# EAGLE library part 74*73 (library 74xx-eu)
Dual J-K FLIP FLOP, clear

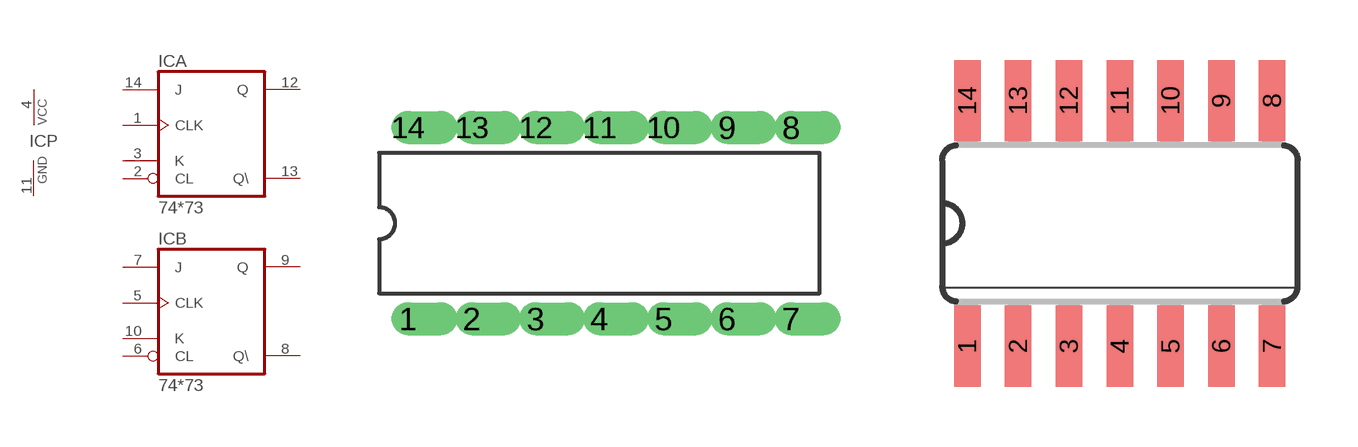
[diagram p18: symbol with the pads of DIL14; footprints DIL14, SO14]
Designator prefix IC; gates A=7473 B=7473 P=PWRN

## 74HC73N, 74HCT73N, 74LS73N  [DIL14]
1  A:CLK  in
2  A:CL  in
3  A:K  in
4  P:VCC  pwr
5  B:CLK  in
6  B:CL  in
7  B:J  in
8  B:Q\  out
9  B:Q  out
10  B:K  in
11  P:GND  pwr
12  A:Q  out
13  A:Q\  out
14  A:J  in

## 74HC73D, 74HCT73D, 74LS73D  [SO14]
Pads as for DIL14

## Footprint DIL14 (pad centres in mm)
Dual In Line
drill 0.8 offset: 1 -7.62,-3.81; 2 -5.08,-3.81; 3 -2.54,-3.81; 4 0,-3.81; 5 2.54,-3.81; 6 5.08,-3.81; 7 7.62,-3.81; 8 7.62,3.81; 9 5.08,3.81; 10 2.54,3.81; 11 0,3.81; 12 -2.54,3.81; 13 -5.08,3.81; 14 -7.62,3.81

## Footprint SO14 (pad centres in mm)
Small Outline package 150 mil
smd 0.66 x 2.032: 1 -3.81,-3.073; 2 -2.54,-3.073; 3 -1.27,-3.073; 4 0,-3.073; 5 1.27,-3.073; 6 2.54,-3.073; 7 3.81,-3.073; 8 3.81,3.073; 9 2.54,3.073; 10 1.27,3.073; 11 0,3.073; 12 -1.27,3.073; 13 -2.54,3.073; 14 -3.81,3.073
